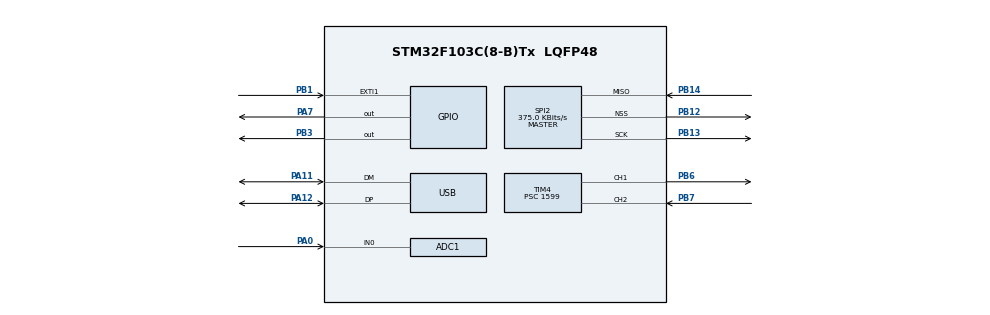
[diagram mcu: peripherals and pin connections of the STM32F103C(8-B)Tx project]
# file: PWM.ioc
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ADC1.Channel-0\#ChannelRegularConversion=ADC_CHANNEL_0
ADC1.ContinuousConvMode=ENABLE
ADC1.DataAlign=ADC_DATAALIGN_RIGHT
ADC1.DiscontinuousConvMode=DISABLE
ADC1.EnableAnalogWatchDog=false
ADC1.EnableRegularConversion=ENABLE
ADC1.ExternalTrigConv=ADC_SOFTWARE_START
ADC1.InjNumberOfConversion=0
ADC1.NbrOfConversion=1
ADC1.NbrOfConversionFlag=1
ADC1.Rank-0\#ChannelRegularConversion=1
ADC1.SamplingTime-0\#ChannelRegularConversion=ADC_SAMPLETIME_1CYCLE_5
ADC1.ScanConvMode=ADC_SCAN_DISABLE
ADC1.master=1
Dma.Request0=TIM4_CH1
Dma.TIM4_CH1.0.Direction=DMA_MEMORY_TO_PERIPH
Dma.TIM4_CH1.0.Instance=DMA1_Channel1
Dma.TIM4_CH1.0.MemDataAlignment=DMA_MDATAALIGN_HALFWORD
Dma.TIM4_CH1.0.MemInc=DMA_MINC_ENABLE
Dma.TIM4_CH1.0.Mode=DMA_CIRCULAR
Dma.TIM4_CH1.0.PeriphDataAlignment=DMA_PDATAALIGN_HALFWORD
Dma.TIM4_CH1.0.PeriphInc=DMA_PINC_DISABLE
Dma.TIM4_CH1.0.Priority=DMA_PRIORITY_HIGH
Mcu.Family=STM32F1
Mcu.Name=STM32F103C(8-B)Tx
Mcu.Package=LQFP48
NVIC.DMA1_Channel1_IRQn=true\:0\:0\:false\:false\:true\:false
NVIC.EXTI1_IRQn=true\:0\:0\:false\:false\:true\:true
NVIC.PriorityGroup=NVIC_PRIORITYGROUP_4
NVIC.TIM3_IRQn=true\:0\:0\:false\:false\:true\:true
NVIC.USB_LP_CAN1_RX0_IRQn=true\:0\:0\:false\:false\:true\:false
PA0-WKUP.Signal=ADCx_IN0
PA11.Mode=Device
PA11.Signal=USB_DM
PA12.Mode=Device
PA12.Signal=USB_DP
PA13.Mode=Serial_Wire
PA13.Signal=SYS_JTMS-SWDIO
PA14.Mode=Serial_Wire
PA14.Signal=SYS_JTCK-SWCLK
PA7.Signal=GPIO_Output
PB1.Signal=GPXTI1
PB12.Mode=NSS_Signal_Hard_Output
PB12.Signal=SPI2_NSS
PB13.Mode=RX_Only_Simplex_Unidirect_Master
PB13.Signal=SPI2_SCK
PB14.Mode=RX_Only_Simplex_Unidirect_Master
PB14.Signal=SPI2_MISO
PB3.GPIO_Speed=GPIO_SPEED_FREQ_HIGH
PB3.PinState=GPIO_PIN_SET
PB3.Signal=GPIO_Output
PB6.Signal=S_TIM4_CH1
PB7.Signal=S_TIM4_CH2
PD0-OSC_IN.Mode=HSE-External-Oscillator
PD0-OSC_IN.Signal=RCC_OSC_IN
PD1-OSC_OUT.Mode=HSE-External-Oscillator
PD1-OSC_OUT.Signal=RCC_OSC_OUT
ProjectManager.HeapSize=0x200
ProjectManager.StackSize=0x400
ProjectManager.TargetToolchain=SW4STM32
RCC.AHBFreq_Value=48000000
RCC.APB1CLKDivider=RCC_HCLK_DIV2
RCC.APB1Freq_Value=24000000
RCC.APB1TimFreq_Value=48000000
RCC.APB2CLKDivider=RCC_HCLK_DIV8
RCC.APB2Freq_Value=6000000
RCC.APB2TimFreq_Value=12000000
RCC.HCLKFreq_Value=48000000
RCC.PLLMUL=RCC_PLL_MUL6
RCC.SYSCLKFreq_VALUE=48000000
RCC.SYSCLKSource=RCC_SYSCLKSOURCE_PLLCLK
RCC.USBFreq_Value=48000000
SH.ADCx_IN0.0=ADC1_IN0,IN0
SH.S_TIM4_CH1.0=TIM4_CH1,Output Compare1 CH1
SH.S_TIM4_CH2.0=TIM4_CH2,TriggerSource_TI2FP2
SPI2.BaudRatePrescaler=SPI_BAUDRATEPRESCALER_64
SPI2.CalculateBaudRate=375.0 KBits/s
SPI2.DataSize=SPI_DATASIZE_16BIT
SPI2.Direction=SPI_DIRECTION_2LINES_RXONLY
SPI2.Mode=SPI_MODE_MASTER
SPI2.VirtualNSS=VM_NSSHARD
SPI2.VirtualType=VM_MASTER
TIM3.Period=100
TIM3.Prescaler=1599
TIM4.AutoReloadPreload=TIM_AUTORELOAD_PRELOAD_ENABLE
TIM4.Channel-Output\ Compare1\ CH1=TIM_CHANNEL_1
TIM4.OCMode_1=TIM_OCMODE_INACTIVE
TIM4.OCPolarity_1=TIM_OCPOLARITY_HIGH
TIM4.Period=100
TIM4.Prescaler=1599
TIM4.TIM_MasterOutputTrigger=TIM_TRGO_OC1REF
USB_DEVICE.CLASS_NAME_FS=CDC
USB_DEVICE.VirtualMode=Cdc
USB_DEVICE.VirtualModeFS=Cdc_FS
VP_TIM3_VS_ClockSourceINT.Mode=Internal
VP_TIM4_VS_ClockSourceINT.Mode=Internal
VP_TIM4_VS_ControllerModeReset.Mode=Reset Mode
VP_USB_DEVICE_VS_USB_DEVICE_CDC_FS.Mode=CDC_FS
board=PWM

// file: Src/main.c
/**
  ******************************************************************************
  * @file           : main.c
  * @brief          : Main program body
  ******************************************************************************
  ** This notice applies to any and all portions of this file
  * that are not between comment pairs USER CODE BEGIN and
  * USER CODE END. Other portions of this file, whether
  * inserted by the user or by software development tools
  * are owned by their respective copyright owners.
  *
  * COPYRIGHT(c) 2018 STMicroelectronics
  *
  * Redistribution and use in source and binary forms, with or without modification,
  * are permitted provided that the following conditions are met:
  *   1. Redistributions of source code must retain the above copyright notice,
  *      this list of conditions and the following disclaimer.
  *   2. Redistributions in binary form must reproduce the above copyright notice,
  *      this list of conditions and the following disclaimer in the documentation
  *      and/or other materials provided with the distribution.
  *   3. Neither the name of STMicroelectronics nor the names of its contributors
  *      may be used to endorse or promote products derived from this software
  *      without specific prior written permission.
  *
  * THIS SOFTWARE IS PROVIDED BY THE COPYRIGHT HOLDERS AND CONTRIBUTORS "AS IS"
  * AND ANY EXPRESS OR IMPLIED WARRANTIES, INCLUDING, BUT NOT LIMITED TO, THE
  * IMPLIED WARRANTIES OF MERCHANTABILITY AND FITNESS FOR A PARTICULAR PURPOSE ARE
  * DISCLAIMED. IN NO EVENT SHALL THE COPYRIGHT HOLDER OR CONTRIBUTORS BE LIABLE
  * FOR ANY DIRECT, INDIRECT, INCIDENTAL, SPECIAL, EXEMPLARY, OR CONSEQUENTIAL
  * DAMAGES (INCLUDING, BUT NOT LIMITED TO, PROCUREMENT OF SUBSTITUTE GOODS OR
  * SERVICES; LOSS OF USE, DATA, OR PROFITS; OR BUSINESS INTERRUPTION) HOWEVER
  * CAUSED AND ON ANY THEORY OF LIABILITY, WHETHER IN CONTRACT, STRICT LIABILITY,
  * OR TORT (INCLUDING NEGLIGENCE OR OTHERWISE) ARISING IN ANY WAY OUT OF THE USE
  * OF THIS SOFTWARE, EVEN IF ADVISED OF THE POSSIBILITY OF SUCH DAMAGE.
  *
  ******************************************************************************
  */
#include "main.h"
#include "stm32f1xx_hal.h"
#include "usb_device.h"

/* USER CODE BEGIN Includes */
#include <stdio.h>
#include "stdlib.h"
#include "angleFiring.h"
#include "DbgMcu.h"
#include "usbd_cdc_if.h"
#include "usbd_def.h"
#include "hardwareLogic.h"
#include "stm32f1xx_hal_dma.h"

/* USER CODE END Includes */

ADC_HandleTypeDef hadc1;
SPI_HandleTypeDef hspi2;
TIM_HandleTypeDef htim3;
TIM_HandleTypeDef htim4;
DMA_HandleTypeDef hdma_tim4_ch1;

/* USER CODE BEGIN PV */
/* Private variables ---------------------------------------------------------*/
#define DESIRED_TEMP								200

#define epsilon 									0.01
#define dt 											0.02 	//200ms loop time
#define MAX 										3600
#define MIN 										-3600
#define Kp 											15
#define Kd 											3
#define Ki 											0

#define TIM4_CCR1_ADDRS 							((uint32_t)0x40000834)
#define MAX_NUM_ELEMENT								127

#define RESET_TIM4_CNT								(htim4.Instance->CNT = 0)

volatile int doPulse=0;

/* USER CODE END PV */

void SystemClock_Config(void);
static void MX_GPIO_Init(void);
static void MX_DMA_Init(void);
static void MX_SPI2_Init(void);
static void MX_TIM3_Init(void);
static void MX_TIM4_Init(void);
static void MX_ADC1_Init(void);
//extern void initialise_monitor_handles(void);

void HAL_TIM_MspPostInit(TIM_HandleTypeDef *htim);

/* USER CODE BEGIN PFP */
/* Private function prototypes -----------------------------------------------*/
static void dmaConfiguration(void);
static float computeFiringPercentageFromRawAdc(float adcValue);
static float PIDcal(float setpoint,float actual_position);
static void DMA_SetConfig(DMA_HandleTypeDef *hdma, uint32_t SrcAddress, uint32_t DstAddress, uint32_t DataLength);
int readData(uint8_t *tempBuff);

int getAdc();
float (*patternCallBack)(float setPoint,float actual_position)= &PIDcal;
uint8_t tempBuff[1]={0};

int adcValue=0;
int percentageVal=0;
int n=1000,x=1000;
volatile int nH=0,pH=0,Busy=0;
/* USER CODE END PFP */

int main(void)
 {
  /* USER CODE BEGIN 1 */
//  initialise_monitor_handles();
//  haltTimerxWhenDebugging(DBG_TIM3_STOP);
//  haltTimerxWhenDebugging(DBG_TIM4_STOP);
  static int state=0;

  /* USER CODE END 1 */

  /* MCU Configuration----------------------------------------------------------*/

  /* Reset of all peripherals, Initializes the Flash interface and the Systick. */
  HAL_Init();

  /* Configure the system clock */
  SystemClock_Config();

  /* Initialize all configured peripherals */
  MX_GPIO_Init();
  MX_SPI2_Init();
  MX_DMA_Init();
  MX_TIM3_Init();
  MX_TIM4_Init();
  MX_ADC1_Init();
  /* USER CODE BEGIN 2 */
  HAL_NVIC_EnableIRQ(SPI2_IRQn);
  MX_USB_DEVICE_Init();
//  float pulse = (*patternCallBack)(DESIRED_TEMP,200);
  dmaConfiguration();
  HAL_GPIO_WritePin(GPIOA, GPIO_PIN_7,GPIO_PIN_RESET);
  DMA_SetConfig(&hdma_tim4_ch1,(uint32_t)DMA_Buffer1,(uint32_t)TIM4_CCR1_ADDRS,DMA_BUFFER_SIZE);

  HAL_NVIC_EnableIRQ(TIM3_IRQn);
  HAL_TIM_Base_Start_IT(&htim3);
  HAL_NVIC_EnableIRQ(DMA1_Channel1_IRQn);

  /* USER CODE END 2 */

  /* Infinite loop */
  while (1)
  {

  /* USER CODE BEGIN 3 */
//		adcValue = getAdc();
//		int percentage = computeFiringPercentageFromRawAdc(adcValue);
//		computeFiringPercentageToTicks(percentage,&nH,&pH,&Busy);

	  	percentageVal = (int)interpretor(&UserRxBufferFS);
	  	computeFiringPercentageToTicks(percentageVal,&nH,&pH,&Busy);
	  	char a[]= "hello";
		if(state==0){
			HAL_NVIC_EnableIRQ(EXTI1_IRQn);
			state=1;
		 }
  }
  /* USER CODE END 3 */

}

void SystemClock_Config(void)
{

  RCC_OscInitTypeDef RCC_OscInitStruct;
  RCC_ClkInitTypeDef RCC_ClkInitStruct;
  RCC_PeriphCLKInitTypeDef PeriphClkInit;

    /**Initializes the CPU, AHB and APB busses clocks
    */
  RCC_OscInitStruct.OscillatorType = RCC_OSCILLATORTYPE_HSE;
  RCC_OscInitStruct.HSEState = RCC_HSE_ON;
  RCC_OscInitStruct.HSEPredivValue = RCC_HSE_PREDIV_DIV1;
  RCC_OscInitStruct.HSIState = RCC_HSI_ON;
  RCC_OscInitStruct.PLL.PLLState = RCC_PLL_ON;
  RCC_OscInitStruct.PLL.PLLSource = RCC_PLLSOURCE_HSE;
  RCC_OscInitStruct.PLL.PLLMUL = RCC_PLL_MUL6;
  if (HAL_RCC_OscConfig(&RCC_OscInitStruct) != HAL_OK)
  {
    _Error_Handler(__FILE__, __LINE__);
  }

    /**Initializes the CPU, AHB and APB busses clocks
    */
  RCC_ClkInitStruct.ClockType = RCC_CLOCKTYPE_HCLK|RCC_CLOCKTYPE_SYSCLK
                              |RCC_CLOCKTYPE_PCLK1|RCC_CLOCKTYPE_PCLK2;
  RCC_ClkInitStruct.SYSCLKSource = RCC_SYSCLKSOURCE_PLLCLK;
  RCC_ClkInitStruct.AHBCLKDivider = RCC_SYSCLK_DIV1;
  RCC_ClkInitStruct.APB1CLKDivider = RCC_HCLK_DIV2;
  RCC_ClkInitStruct.APB2CLKDivider = RCC_HCLK_DIV1;

  if (HAL_RCC_ClockConfig(&RCC_ClkInitStruct, FLASH_LATENCY_1) != HAL_OK)
  {
    _Error_Handler(__FILE__, __LINE__);
  }

  PeriphClkInit.PeriphClockSelection = RCC_PERIPHCLK_USB;
  PeriphClkInit.UsbClockSelection = RCC_USBCLKSOURCE_PLL;
  if (HAL_RCCEx_PeriphCLKConfig(&PeriphClkInit) != HAL_OK)
  {
    _Error_Handler(__FILE__, __LINE__);
  }

    /**Configure the Systick interrupt time
    */
  HAL_SYSTICK_Config(HAL_RCC_GetHCLKFreq()/1000);

    /**Configure the Systick
    */
  HAL_SYSTICK_CLKSourceConfig(SYSTICK_CLKSOURCE_HCLK);

  /* SysTick_IRQn interrupt configuration */
  HAL_NVIC_SetPriority(SysTick_IRQn, 0, 0);
}

/* ADC1 init function */
static void MX_ADC1_Init(void)
{

  ADC_ChannelConfTypeDef sConfig;

    /**Common config
    */
  hadc1.Instance = ADC1;
  hadc1.Init.ScanConvMode = ADC_SCAN_DISABLE;
  hadc1.Init.ContinuousConvMode = ENABLE;
  hadc1.Init.DiscontinuousConvMode = DISABLE;
  hadc1.Init.ExternalTrigConv = ADC_SOFTWARE_START;
  hadc1.Init.DataAlign = ADC_DATAALIGN_RIGHT;
  hadc1.Init.NbrOfConversion = 1;
  if (HAL_ADC_Init(&hadc1) != HAL_OK)
  {
    _Error_Handler(__FILE__, __LINE__);
  }

    /**Configure Regular Channel
    */
  sConfig.Channel = ADC_CHANNEL_0;
  sConfig.Rank = ADC_REGULAR_RANK_1;
  sConfig.SamplingTime = ADC_SAMPLETIME_1CYCLE_5;
  if (HAL_ADC_ConfigChannel(&hadc1, &sConfig) != HAL_OK)
  {
    _Error_Handler(__FILE__, __LINE__);
  }

}

/* TIM3 init function */
static void MX_TIM3_Init(void)
{

  TIM_ClockConfigTypeDef sClockSourceConfig;
  TIM_MasterConfigTypeDef sMasterConfig;
  TIM_OC_InitTypeDef sConfigOC;

  htim3.Instance = TIM3;
  htim3.Init.Prescaler = 65534;
  htim3.Init.CounterMode = TIM_COUNTERMODE_UP;
  htim3.Init.Period = 2000;
  htim3.Init.ClockDivision = TIM_CLOCKDIVISION_DIV1;
  htim3.Init.AutoReloadPreload = TIM_AUTORELOAD_PRELOAD_DISABLE;
  if (HAL_TIM_Base_Init(&htim3) != HAL_OK)
  {
    _Error_Handler(__FILE__, __LINE__);
  }

  sClockSourceConfig.ClockSource = TIM_CLOCKSOURCE_INTERNAL;
  if (HAL_TIM_ConfigClockSource(&htim3, &sClockSourceConfig) != HAL_OK)
  {
    _Error_Handler(__FILE__, __LINE__);
  }

  if (HAL_TIM_PWM_Init(&htim3) != HAL_OK)
  {
    _Error_Handler(__FILE__, __LINE__);
  }

  sMasterConfig.MasterOutputTrigger = TIM_TRGO_RESET;
  sMasterConfig.MasterSlaveMode = TIM_MASTERSLAVEMODE_DISABLE;
  if (HAL_TIMEx_MasterConfigSynchronization(&htim3, &sMasterConfig) != HAL_OK)
   {
     _Error_Handler(__FILE__, __LINE__);
   }

}

/* TIM4 init function */
static void MX_TIM4_Init(void)
{

  TIM_ClockConfigTypeDef sClockSourceConfig;
  TIM_SlaveConfigTypeDef sSlaveConfig;
  TIM_MasterConfigTypeDef sMasterConfig;
  TIM_OC_InitTypeDef sConfigOC;

  htim4.Instance = TIM4;
  htim4.Init.Prescaler = 9599;
  htim4.Init.CounterMode = TIM_COUNTERMODE_UP;
  htim4.Init.Period = 500;
  htim4.Init.ClockDivision = TIM_CLOCKDIVISION_DIV1;
  htim4.Init.AutoReloadPreload = TIM_AUTORELOAD_PRELOAD_ENABLE;
  if (HAL_TIM_Base_Init(&htim4) != HAL_OK)
  {
    _Error_Handler(__FILE__, __LINE__);
  }

  sClockSourceConfig.ClockSource = TIM_CLOCKSOURCE_INTERNAL;
  if (HAL_TIM_ConfigClockSource(&htim4, &sClockSourceConfig) != HAL_OK)
  {
    _Error_Handler(__FILE__, __LINE__);
  }

  if (HAL_TIM_OC_Init(&htim4) != HAL_OK)
  {
    _Error_Handler(__FILE__, __LINE__);
  }

  sSlaveConfig.SlaveMode = TIM_SLAVEMODE_RESET;
  sSlaveConfig.InputTrigger = TIM_TS_TI2FP2;
  sSlaveConfig.TriggerPolarity = TIM_TRIGGERPOLARITY_FALLING;
  sSlaveConfig.TriggerFilter = 0;
  if (HAL_TIM_SlaveConfigSynchronization(&htim4, &sSlaveConfig) != HAL_OK)
  {
    _Error_Handler(__FILE__, __LINE__);
  }

  sMasterConfig.MasterOutputTrigger = TIM_TRGO_OC1REF;
  sMasterConfig.MasterSlaveMode = TIM_MASTERSLAVEMODE_DISABLE;
  if (HAL_TIMEx_MasterConfigSynchronization(&htim4, &sMasterConfig) != HAL_OK)
  {
    _Error_Handler(__FILE__, __LINE__);
  }

  sConfigOC.OCMode = TIM_OCMODE_TOGGLE;
//  sConfigOC.Pulse = 50;
  sConfigOC.OCPolarity = TIM_OCPOLARITY_HIGH;
  sConfigOC.OCFastMode = TIM_OCFAST_DISABLE;
  if (HAL_TIM_OC_ConfigChannel(&htim4, &sConfigOC, TIM_CHANNEL_1) != HAL_OK)
  {
    _Error_Handler(__FILE__, __LINE__);
  }

  HAL_TIM_MspPostInit(&htim4);

}

static void MX_DMA_Init(void)
{
  /* DMA controller clock enable */
  __HAL_RCC_DMA1_CLK_ENABLE();

  /* DMA interrupt init */
  /* DMA1_Channel1_IRQn interrupt configuration */
  HAL_NVIC_SetPriority(DMA1_Channel1_IRQn, 0, 0);
}

/** Configure pins as
        * Analog
        * Input
        * Output
        * EVENT_OUT
        * EXTI
*/
static void MX_GPIO_Init(void)
{

  GPIO_InitTypeDef GPIO_InitStruct;

  /* GPIO Ports Clock Enable */
  __HAL_RCC_GPIOD_CLK_ENABLE();
  __HAL_RCC_GPIOA_CLK_ENABLE();
  __HAL_RCC_GPIOB_CLK_ENABLE();

  /*Configure GPIO pin Output Level */
  HAL_GPIO_WritePin(GPIOA, GPIO_PIN_7, GPIO_PIN_RESET);

  /*Configure GPIO pin Output Level */
  HAL_GPIO_WritePin(GPIOB, GPIO_PIN_3, GPIO_PIN_SET);

  /*Configure GPIO pin : PA7 */
  GPIO_InitStruct.Pin = GPIO_PIN_7;
  GPIO_InitStruct.Mode = GPIO_MODE_OUTPUT_PP;
  GPIO_InitStruct.Pull = GPIO_NOPULL;
  GPIO_InitStruct.Speed = GPIO_SPEED_FREQ_HIGH;
  HAL_GPIO_Init(GPIOA, &GPIO_InitStruct);

  /*Configure GPIO pin : PB1 */
  GPIO_InitStruct.Pin = GPIO_PIN_1;
  GPIO_InitStruct.Mode = GPIO_MODE_IT_FALLING;
  GPIO_InitStruct.Pull = GPIO_NOPULL;
  HAL_GPIO_Init(GPIOB, &GPIO_InitStruct);

  /*Configure GPIO pin : PB3 */
  GPIO_InitStruct.Pin = GPIO_PIN_3;
  GPIO_InitStruct.Mode = GPIO_MODE_OUTPUT_PP;
  GPIO_InitStruct.Pull = GPIO_NOPULL;
  GPIO_InitStruct.Speed = GPIO_SPEED_FREQ_HIGH;
  HAL_GPIO_Init(GPIOB, &GPIO_InitStruct);

  /* EXTI interrupt init*/
  HAL_NVIC_SetPriority(EXTI1_IRQn, 0, 0);

}

/* USER CODE BEGIN 4 */
static void MX_SPI2_Init(void)
{

  /* SPI2 parameter configuration*/
  hspi2.Instance = SPI2;
  hspi2.Init.Mode = SPI_MODE_MASTER;
  hspi2.Init.Direction = SPI_DIRECTION_2LINES_RXONLY;
  hspi2.Init.DataSize = SPI_DATASIZE_16BIT;
  hspi2.Init.CLKPolarity = SPI_POLARITY_LOW;
  hspi2.Init.CLKPhase = SPI_PHASE_1EDGE;
  hspi2.Init.NSS = SPI_NSS_HARD_OUTPUT;
  hspi2.Init.BaudRatePrescaler = SPI_BAUDRATEPRESCALER_128;
  hspi2.Init.FirstBit = SPI_FIRSTBIT_MSB;
  hspi2.Init.TIMode = SPI_TIMODE_DISABLE;
  hspi2.Init.CRCCalculation = SPI_CRCCALCULATION_DISABLE;
  hspi2.Init.CRCPolynomial = 10;
  if (HAL_SPI_Init(&hspi2) != HAL_OK)
  {
    _Error_Handler(__FILE__, __LINE__);
  }

}
/**
* @brief This function handles EXTI line1 interrupt.
*/
void EXTI1_IRQHandler(void)
{
  /* USER CODE BEGIN EXTI1_IRQn 0 */
	static int state=1;

	/*Configure GPIO pin Output Level */
	if((EXTI->PR&0x02)==0x02){
		HAL_GPIO_WritePin(GPIOA,GPIO_PIN_7,GPIO_PIN_SET);
		HAL_GPIO_WritePin(GPIOA,GPIO_PIN_7,GPIO_PIN_RESET);

		doPulse=1;
		computeValueToPutIntoDmaBufferFromTicks(&nH,&pH,Busy);

#ifdef DEBUG_LOG
		printf("\nraw ADC: %f",adcValue);
		printf("\nfiring percentage: %i",percentage);
		printf("\nt1: %i",nH);
		printf("\nt2: %i",pH);

#endif
	/* 	When the power is off, the firing angle is set to a very large value so that the CNT will never reach the value.
	 * 	However, the OC will also never reaches the value to ask DMA to transfer another set of data.
	 * 	So, CCR is hard-coded with a value to restart the DMA transfer when the power is on.
	 *
	 */
		if(nH==-1||pH==-1){
			disableDmaAndOcFiring();
			state=1;
		}
		else{
			if(state==1){
				state=0;
				HAL_TIM_OC_Start(&htim4, TIM_CHANNEL_1);
				RESET_TIM4_CNT;
				__HAL_DMA_ENABLE(&hdma_tim4_ch1);

//				htim4.Instance->EGR |= 1<<1;		//set CC1F flag to request DMA.
			}
			else
				HAL_TIM_OC_Start(&htim4, TIM_CHANNEL_1);
		}
  /* USER CODE END EXTI1_IRQn 0 */
	}
  HAL_GPIO_EXTI_IRQHandler(GPIO_PIN_1);
  /* USER CODE BEGIN EXTI1_IRQn 1 */

  /* USER CODE END EXTI1_IRQn 1 */
}

/**
* @brief This function handles TIM3 global interrupt.
*/
void TIM3_IRQHandler(void)
{
  /* USER CODE BEGIN TIM3_IRQn 0 */
	htim3.Instance->SR &= 0;
	readData(tempBuff);
  /* USER CODE END TIM3_IRQn 0 */
  HAL_TIM_IRQHandler(&htim3);
  /* USER CODE BEGIN TIM3_IRQn 1 */

  /* USER CODE END TIM3_IRQn 1 */
}

int8_t CDC_Receive_FS(uint8_t* Buf, uint32_t *Len)
{
	/* USER CODE BEGIN 6 */
	int i=0,y=0;

	while(Buf[i]!=0){
		USBD_CDC_SetRxBuffer(&hUsbDeviceFS, &Buf[i]);
		USBD_CDC_ReceivePacket(&hUsbDeviceFS);
		i++;
	}
	return (USBD_OK);
	  /* USER CODE END 6 */
	}

int readData(uint8_t *tempBuff){
	uint8_t data[2]={0};
	static int i = 0;
	uint16_t value;
	HAL_StatusTypeDef state;
//	while((hspi2.Instance->SR & 1) == 0);

	HAL_GPIO_WritePin(GPIOB,GPIO_PIN_12,RESET);
	state = HAL_SPI_Receive(&hspi2,data,1,1000);
	HAL_GPIO_WritePin(GPIOB,GPIO_PIN_12,SET);
	if(data[0]&4){
		return 0;
	}
	asm volatile("dmb":::"memory");
	value = (data[1]<<8 | data[0]);
	asm volatile("dmb":::"memory");
	value = ((0x0fff & (value>>3))/4);
	asm volatile("dmb":::"memory");
	tempBuff[0]=value;
  	CDC_Transmit_FS(tempBuff,1);

}

// Function for ADC
int getAdc()
{
	HAL_ADC_Start(&hadc1);

	if (HAL_ADC_PollForConversion(&hadc1, 1)!=HAL_OK)
	{
	}

	while ((HAL_ADC_GetState(&hadc1) & HAL_ADC_STATE_REG_EOC ) != HAL_ADC_STATE_REG_EOC);
	return HAL_ADC_GetValue(&hadc1);
}

static void dmaConfiguration(void)
{

	htim4.Instance->DIER |= TIM_DIER_CC1DE|TIM_DIER_TDE;  //Enable trigger DMA request and OC DMA request enable.
	htim4.Instance->EGR |= TIM_EGR_CC1G|TIM_EGR_TG;		  //Compare 1 generation: Corresponding interrupt or DMA request is sent if enabled.

}

static float computeFiringPercentageFromRawAdc(float adcValue)
{
	if(adcValue>4000)
		adcValue = 4000;
	if(adcValue<300)
		adcValue = 0;
	float firingAngle = ((adcValue/4000)*100);
	return firingAngle;
}

static float PIDcal(float setpoint,float actual_position)
{
	static float pre_error= 0;
	static float integral=0;
	float error;
	float derivative;
	float output;
	//CaculateP,I,D
	error = setpoint - actual_position;
	//In case of error too small then stop integration
	if(abs(error)> epsilon)
	{
		integral = integral + error;
	}
	derivative = (error - pre_error);
	output = Kp * error + Ki * integral + Kd * derivative;
	//Saturation Filter
	if(output > MAX)
	{
		output = MAX;
	}
	else if(output < MIN)
	{
		output= MIN;
	}
	//Update error
	pre_error = error;
	float pulseWidth = ((output / 3600) * 100);
	return pulseWidth;

}

static void DMA_SetConfig(DMA_HandleTypeDef *hdma, uint32_t SrcAddress, uint32_t DstAddress, uint32_t DataLength)
{
  /* Clear all flags */
  hdma->DmaBaseAddress->IFCR = (DMA_ISR_GIF1 << hdma->ChannelIndex);

  /* Configure DMA Channel data length */
  hdma->Instance->CNDTR = DataLength;

  /* Memory to Peripheral */
  if((hdma->Init.Direction) == DMA_MEMORY_TO_PERIPH)
  {
    /* Configure DMA Channel destination address */
    hdma->Instance->CPAR = DstAddress;

    /* Configure DMA Channel source address */
    hdma->Instance->CMAR = SrcAddress;
  }
  /* Peripheral to Memory */
  else
  {
    /* Configure DMA Channel source address */
    hdma->Instance->CPAR = SrcAddress;

    /* Configure DMA Channel destination address */
    hdma->Instance->CMAR = DstAddress;
  }
}
/* USER CODE END 4 */

void _Error_Handler(char *file, int line)
{
  while(1)
  {
  }
}

/************************ (C) COPYRIGHT STMicroelectronics *****END OF FILE****/
